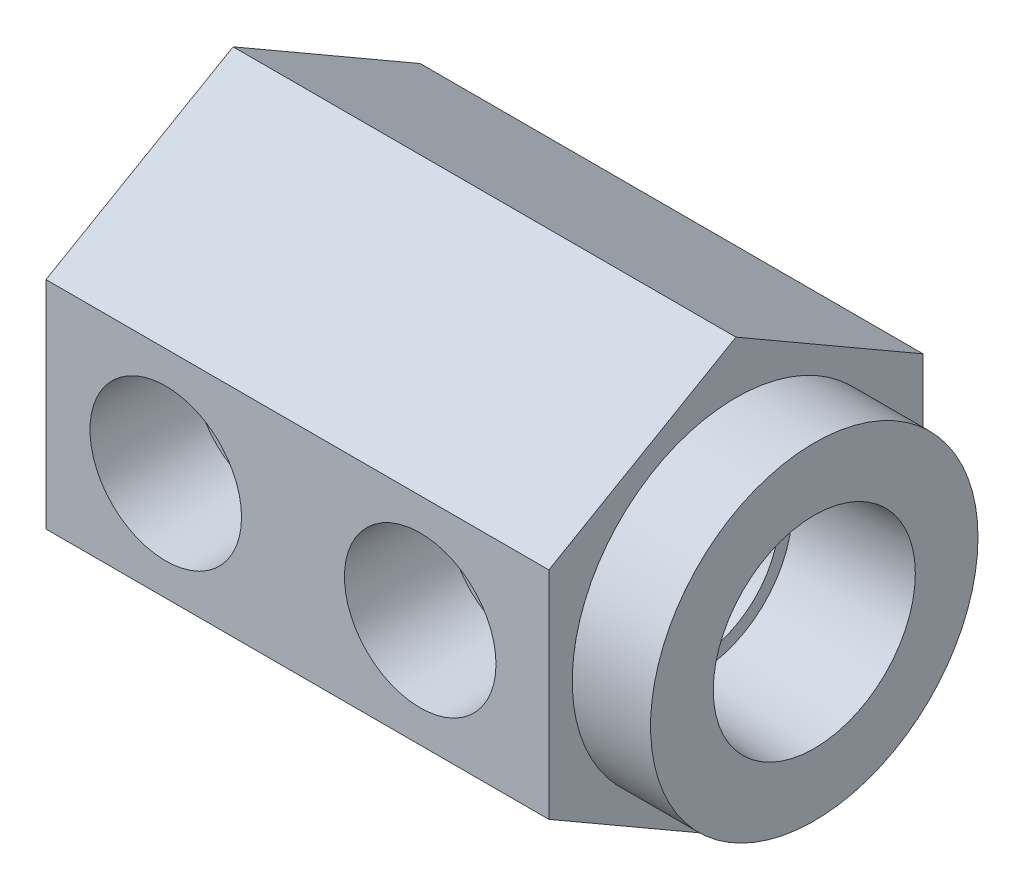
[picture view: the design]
ISO-10303-21;
HEADER;
FILE_DESCRIPTION(('STEP AP214'),'2;1');
FILE_NAME('part.step','',(''),(''),'','','');
FILE_SCHEMA(('AUTOMOTIVE_DESIGN { 1 0 10303 214 1 1 1 1 }'));
ENDSEC;
DATA;
#1=APPLICATION_CONTEXT('core data for automotive mechanical design processes');
#2=APPLICATION_PROTOCOL_DEFINITION('international standard','automotive_design',2000,#1);
#3=PRODUCT_CONTEXT('',#1,'mechanical');
#4=PRODUCT('Part','Part','',(#3));
#5=PRODUCT_RELATED_PRODUCT_CATEGORY('part','',(#4));
#6=PRODUCT_DEFINITION_FORMATION('','',#4);
#7=PRODUCT_DEFINITION_CONTEXT('part definition',#1,'design');
#8=PRODUCT_DEFINITION('design','',#6,#7);
#9=PRODUCT_DEFINITION_SHAPE('','',#8);
#10=(LENGTH_UNIT() NAMED_UNIT(*) SI_UNIT(.MILLI.,.METRE.));
#11=(NAMED_UNIT(*) PLANE_ANGLE_UNIT() SI_UNIT($,.RADIAN.));
#12=(NAMED_UNIT(*) SI_UNIT($,.STERADIAN.) SOLID_ANGLE_UNIT());
#13=UNCERTAINTY_MEASURE_WITH_UNIT(LENGTH_MEASURE(1.E-05),#10,'distance_accuracy_value','');
#14=(GEOMETRIC_REPRESENTATION_CONTEXT(3) GLOBAL_UNCERTAINTY_ASSIGNED_CONTEXT((#13)) GLOBAL_UNIT_ASSIGNED_CONTEXT((#10,
#11,#12)) REPRESENTATION_CONTEXT('',''));
#15=CARTESIAN_POINT('',(0.,0.,0.));
#16=DIRECTION('',(0.,0.,1.));
#17=DIRECTION('',(1.,0.,0.));
#18=AXIS2_PLACEMENT_3D('',#15,#16,#17);
#19=CARTESIAN_POINT('',(39.44747,0.,0.));
#20=DIRECTION('',(1.,0.,0.));
#21=DIRECTION('',(0.,0.,-1.));
#22=AXIS2_PLACEMENT_3D('',#19,#20,#21);
#23=PLANE('',#22);
#24=CARTESIAN_POINT('',(39.44747,0.,0.));
#25=DIRECTION('',(1.,0.,0.));
#26=DIRECTION('',(0.,0.,-1.));
#27=AXIS2_PLACEMENT_3D('',#24,#25,#26);
#28=CIRCLE('',#27,11.1125);
#29=CARTESIAN_POINT('',(39.44747,0.,-11.1125));
#30=VERTEX_POINT('',#29);
#31=EDGE_CURVE('E137',#30,#30,#28,.T.);
#32=ORIENTED_EDGE('',*,*,#31,.T.);
#33=EDGE_LOOP('',(#32));
#34=FACE_BOUND('',#33,.T.);
#35=CARTESIAN_POINT('',(39.44747,0.,0.));
#36=DIRECTION('',(-1.,0.,0.));
#37=DIRECTION('',(0.,0.,1.));
#38=AXIS2_PLACEMENT_3D('',#35,#36,#37);
#39=CIRCLE('',#38,6.85806655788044);
#40=CARTESIAN_POINT('',(39.44747,0.,6.85806655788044));
#41=VERTEX_POINT('',#40);
#42=EDGE_CURVE('E297',#41,#41,#39,.T.);
#43=ORIENTED_EDGE('',*,*,#42,.T.);
#44=EDGE_LOOP('',(#43));
#45=FACE_BOUND('',#44,.T.);
#46=ADVANCED_FACE('F35',(#34,#45),#23,.T.);
#47=CARTESIAN_POINT('',(34.13125,-7.33234841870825,12.7));
#48=DIRECTION('',(1.,0.,0.));
#49=DIRECTION('',(0.,0.,-1.));
#50=AXIS2_PLACEMENT_3D('',#47,#48,#49);
#51=PLANE('',#50);
#52=DIRECTION('',(0.,-1.,0.));
#53=VECTOR('',#52,1.);
#54=CARTESIAN_POINT('',(34.13125,7.33234841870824,12.7));
#55=LINE('',#54,#53);
#56=CARTESIAN_POINT('',(34.13125,7.33234841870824,12.7));
#57=VERTEX_POINT('',#56);
#58=CARTESIAN_POINT('',(34.13125,-7.33234841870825,12.7));
#59=VERTEX_POINT('',#58);
#60=EDGE_CURVE('E145',#57,#59,#55,.T.);
#61=ORIENTED_EDGE('',*,*,#60,.T.);
#62=DIRECTION('',(0.,-0.5,-0.866025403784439));
#63=VECTOR('',#62,1.);
#64=CARTESIAN_POINT('',(34.13125,-7.33234841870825,12.7));
#65=LINE('',#64,#63);
#66=CARTESIAN_POINT('',(34.13125,-14.6646968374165,0.));
#67=VERTEX_POINT('',#66);
#68=EDGE_CURVE('E95',#59,#67,#65,.T.);
#69=ORIENTED_EDGE('',*,*,#68,.T.);
#70=DIRECTION('',(0.,0.5,-0.866025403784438));
#71=VECTOR('',#70,1.);
#72=CARTESIAN_POINT('',(34.13125,-14.6646968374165,0.));
#73=LINE('',#72,#71);
#74=CARTESIAN_POINT('',(34.13125,-7.33234841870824,-12.7));
#75=VERTEX_POINT('',#74);
#76=EDGE_CURVE('E112',#67,#75,#73,.T.);
#77=ORIENTED_EDGE('',*,*,#76,.T.);
#78=DIRECTION('',(0.,1.,0.));
#79=VECTOR('',#78,1.);
#80=CARTESIAN_POINT('',(34.13125,-7.33234841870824,-12.7));
#81=LINE('',#80,#79);
#82=CARTESIAN_POINT('',(34.13125,7.33234841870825,-12.7));
#83=VERTEX_POINT('',#82);
#84=EDGE_CURVE('E104',#75,#83,#81,.T.);
#85=ORIENTED_EDGE('',*,*,#84,.T.);
#86=DIRECTION('',(0.,0.5,0.866025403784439));
#87=VECTOR('',#86,1.);
#88=CARTESIAN_POINT('',(34.13125,7.33234841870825,-12.7));
#89=LINE('',#88,#87);
#90=CARTESIAN_POINT('',(34.13125,14.6646968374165,0.));
#91=VERTEX_POINT('',#90);
#92=EDGE_CURVE('E109',#83,#91,#89,.T.);
#93=ORIENTED_EDGE('',*,*,#92,.T.);
#94=DIRECTION('',(0.,-0.5,0.866025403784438));
#95=VECTOR('',#94,1.);
#96=CARTESIAN_POINT('',(34.13125,14.6646968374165,0.));
#97=LINE('',#96,#95);
#98=EDGE_CURVE('E59',#91,#57,#97,.T.);
#99=ORIENTED_EDGE('',*,*,#98,.T.);
#100=EDGE_LOOP('',(#61,#69,#77,#85,#93,#99));
#101=FACE_BOUND('',#100,.T.);
#102=CARTESIAN_POINT('',(34.13125,0.,0.));
#103=DIRECTION('',(1.,0.,0.));
#104=DIRECTION('',(0.,0.,-1.));
#105=AXIS2_PLACEMENT_3D('',#102,#103,#104);
#106=CIRCLE('',#105,11.1125);
#107=CARTESIAN_POINT('',(34.13125,0.,-11.1125));
#108=VERTEX_POINT('',#107);
#109=EDGE_CURVE('E290',#108,#108,#106,.T.);
#110=ORIENTED_EDGE('',*,*,#109,.F.);
#111=EDGE_LOOP('',(#110));
#112=FACE_BOUND('',#111,.T.);
#113=ADVANCED_FACE('F106',(#101,#112),#51,.T.);
#114=CARTESIAN_POINT('',(34.13125,7.33234841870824,12.7));
#115=DIRECTION('',(0.,0.,-1.));
#116=DIRECTION('',(0.,1.,0.));
#117=AXIS2_PLACEMENT_3D('',#114,#115,#116);
#118=PLANE('',#117);
#119=CARTESIAN_POINT('',(8.128,0.,12.7));
#120=DIRECTION('',(0.,0.,1.));
#121=DIRECTION('',(1.,0.,0.));
#122=AXIS2_PLACEMENT_3D('',#119,#120,#121);
#123=CIRCLE('',#122,5.1435);
#124=CARTESIAN_POINT('',(13.2715,0.,12.7));
#125=VERTEX_POINT('',#124);
#126=EDGE_CURVE('E319',#125,#125,#123,.T.);
#127=ORIENTED_EDGE('',*,*,#126,.F.);
#128=EDGE_LOOP('',(#127));
#129=FACE_BOUND('',#128,.T.);
#130=CARTESIAN_POINT('',(25.4,0.,12.7));
#131=DIRECTION('',(0.,0.,1.));
#132=DIRECTION('',(1.,0.,0.));
#133=AXIS2_PLACEMENT_3D('',#130,#131,#132);
#134=CIRCLE('',#133,5.1435);
#135=CARTESIAN_POINT('',(30.5435,0.,12.7));
#136=VERTEX_POINT('',#135);
#137=EDGE_CURVE('E310',#136,#136,#134,.T.);
#138=ORIENTED_EDGE('',*,*,#137,.F.);
#139=EDGE_LOOP('',(#138));
#140=FACE_BOUND('',#139,.T.);
#141=DIRECTION('',(0.,-1.,0.));
#142=VECTOR('',#141,1.);
#143=CARTESIAN_POINT('',(0.,7.33234841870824,12.7));
#144=LINE('',#143,#142);
#145=CARTESIAN_POINT('',(0.,7.33234841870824,12.7));
#146=VERTEX_POINT('',#145);
#147=CARTESIAN_POINT('',(0.,-7.33234841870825,12.7));
#148=VERTEX_POINT('',#147);
#149=EDGE_CURVE('E133',#146,#148,#144,.T.);
#150=ORIENTED_EDGE('',*,*,#149,.T.);
#151=DIRECTION('',(-1.,0.,0.));
#152=VECTOR('',#151,1.);
#153=CARTESIAN_POINT('',(34.13125,-7.33234841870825,12.7));
#154=LINE('',#153,#152);
#155=EDGE_CURVE('E152',#59,#148,#154,.T.);
#156=ORIENTED_EDGE('',*,*,#155,.F.);
#157=ORIENTED_EDGE('',*,*,#60,.F.);
#158=DIRECTION('',(-1.,0.,0.));
#159=VECTOR('',#158,1.);
#160=CARTESIAN_POINT('',(34.13125,7.33234841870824,12.7));
#161=LINE('',#160,#159);
#162=EDGE_CURVE('E129',#57,#146,#161,.T.);
#163=ORIENTED_EDGE('',*,*,#162,.T.);
#164=EDGE_LOOP('',(#150,#156,#157,#163));
#165=FACE_BOUND('',#164,.T.);
#166=ADVANCED_FACE('F37',(#129,#140,#165),#118,.F.);
#167=CARTESIAN_POINT('',(34.13125,-7.33234841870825,12.7));
#168=DIRECTION('',(0.,0.866025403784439,-0.5));
#169=DIRECTION('',(0.,0.5,0.866025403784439));
#170=AXIS2_PLACEMENT_3D('',#167,#168,#169);
#171=PLANE('',#170);
#172=DIRECTION('',(0.,-0.5,-0.866025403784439));
#173=VECTOR('',#172,1.);
#174=CARTESIAN_POINT('',(0.,-7.33234841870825,12.7));
#175=LINE('',#174,#173);
#176=CARTESIAN_POINT('',(0.,-14.6646968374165,0.));
#177=VERTEX_POINT('',#176);
#178=EDGE_CURVE('E136',#148,#177,#175,.T.);
#179=ORIENTED_EDGE('',*,*,#178,.T.);
#180=DIRECTION('',(-1.,0.,0.));
#181=VECTOR('',#180,1.);
#182=CARTESIAN_POINT('',(34.13125,-14.6646968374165,0.));
#183=LINE('',#182,#181);
#184=EDGE_CURVE('E149',#67,#177,#183,.T.);
#185=ORIENTED_EDGE('',*,*,#184,.F.);
#186=ORIENTED_EDGE('',*,*,#68,.F.);
#187=ORIENTED_EDGE('',*,*,#155,.T.);
#188=EDGE_LOOP('',(#179,#185,#186,#187));
#189=FACE_BOUND('',#188,.T.);
#190=ADVANCED_FACE('F275',(#189),#171,.F.);
#191=CARTESIAN_POINT('',(34.13125,-14.6646968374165,0.));
#192=DIRECTION('',(0.,0.866025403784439,0.5));
#193=DIRECTION('',(0.,-0.5,0.866025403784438));
#194=AXIS2_PLACEMENT_3D('',#191,#192,#193);
#195=PLANE('',#194);
#196=DIRECTION('',(0.,0.5,-0.866025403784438));
#197=VECTOR('',#196,1.);
#198=CARTESIAN_POINT('',(0.,-14.6646968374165,0.));
#199=LINE('',#198,#197);
#200=CARTESIAN_POINT('',(0.,-7.33234841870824,-12.7));
#201=VERTEX_POINT('',#200);
#202=EDGE_CURVE('E139',#177,#201,#199,.T.);
#203=ORIENTED_EDGE('',*,*,#202,.T.);
#204=DIRECTION('',(-1.,0.,0.));
#205=VECTOR('',#204,1.);
#206=CARTESIAN_POINT('',(34.13125,-7.33234841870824,-12.7));
#207=LINE('',#206,#205);
#208=EDGE_CURVE('E124',#75,#201,#207,.T.);
#209=ORIENTED_EDGE('',*,*,#208,.F.);
#210=ORIENTED_EDGE('',*,*,#76,.F.);
#211=ORIENTED_EDGE('',*,*,#184,.T.);
#212=EDGE_LOOP('',(#203,#209,#210,#211));
#213=FACE_BOUND('',#212,.T.);
#214=ADVANCED_FACE('F272',(#213),#195,.F.);
#215=CARTESIAN_POINT('',(34.13125,-7.33234841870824,-12.7));
#216=DIRECTION('',(0.,0.,1.));
#217=DIRECTION('',(0.,-1.,0.));
#218=AXIS2_PLACEMENT_3D('',#215,#216,#217);
#219=PLANE('',#218);
#220=CARTESIAN_POINT('',(8.128,0.,-12.7));
#221=DIRECTION('',(0.,0.,-1.));
#222=DIRECTION('',(0.,1.,0.));
#223=AXIS2_PLACEMENT_3D('',#220,#221,#222);
#224=CIRCLE('',#223,5.1435);
#225=CARTESIAN_POINT('',(8.128,5.1435,-12.7));
#226=VERTEX_POINT('',#225);
#227=EDGE_CURVE('E328',#226,#226,#224,.T.);
#228=ORIENTED_EDGE('',*,*,#227,.F.);
#229=EDGE_LOOP('',(#228));
#230=FACE_BOUND('',#229,.T.);
#231=DIRECTION('',(0.,1.,0.));
#232=VECTOR('',#231,1.);
#233=CARTESIAN_POINT('',(0.,-7.33234841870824,-12.7));
#234=LINE('',#233,#232);
#235=CARTESIAN_POINT('',(0.,7.33234841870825,-12.7));
#236=VERTEX_POINT('',#235);
#237=EDGE_CURVE('E121',#201,#236,#234,.T.);
#238=ORIENTED_EDGE('',*,*,#237,.T.);
#239=DIRECTION('',(-1.,0.,0.));
#240=VECTOR('',#239,1.);
#241=CARTESIAN_POINT('',(34.13125,7.33234841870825,-12.7));
#242=LINE('',#241,#240);
#243=EDGE_CURVE('E118',#83,#236,#242,.T.);
#244=ORIENTED_EDGE('',*,*,#243,.F.);
#245=ORIENTED_EDGE('',*,*,#84,.F.);
#246=ORIENTED_EDGE('',*,*,#208,.T.);
#247=EDGE_LOOP('',(#238,#244,#245,#246));
#248=FACE_BOUND('',#247,.T.);
#249=ADVANCED_FACE('F119',(#230,#248),#219,.F.);
#250=CARTESIAN_POINT('',(34.13125,7.33234841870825,-12.7));
#251=DIRECTION('',(0.,-0.866025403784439,0.5));
#252=DIRECTION('',(0.,-0.5,-0.866025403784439));
#253=AXIS2_PLACEMENT_3D('',#250,#251,#252);
#254=PLANE('',#253);
#255=DIRECTION('',(0.,0.5,0.866025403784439));
#256=VECTOR('',#255,1.);
#257=CARTESIAN_POINT('',(0.,7.33234841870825,-12.7));
#258=LINE('',#257,#256);
#259=CARTESIAN_POINT('',(0.,14.6646968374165,0.));
#260=VERTEX_POINT('',#259);
#261=EDGE_CURVE('E142',#236,#260,#258,.T.);
#262=ORIENTED_EDGE('',*,*,#261,.T.);
#263=DIRECTION('',(-1.,0.,0.));
#264=VECTOR('',#263,1.);
#265=CARTESIAN_POINT('',(34.13125,14.6646968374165,0.));
#266=LINE('',#265,#264);
#267=EDGE_CURVE('E125',#91,#260,#266,.T.);
#268=ORIENTED_EDGE('',*,*,#267,.F.);
#269=ORIENTED_EDGE('',*,*,#92,.F.);
#270=ORIENTED_EDGE('',*,*,#243,.T.);
#271=EDGE_LOOP('',(#262,#268,#269,#270));
#272=FACE_BOUND('',#271,.T.);
#273=ADVANCED_FACE('F127',(#272),#254,.F.);
#274=CARTESIAN_POINT('',(34.13125,14.6646968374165,0.));
#275=DIRECTION('',(0.,-0.866025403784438,-0.5));
#276=DIRECTION('',(0.,0.5,-0.866025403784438));
#277=AXIS2_PLACEMENT_3D('',#274,#275,#276);
#278=PLANE('',#277);
#279=DIRECTION('',(0.,-0.5,0.866025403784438));
#280=VECTOR('',#279,1.);
#281=CARTESIAN_POINT('',(0.,14.6646968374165,0.));
#282=LINE('',#281,#280);
#283=EDGE_CURVE('E86',#260,#146,#282,.T.);
#284=ORIENTED_EDGE('',*,*,#283,.T.);
#285=ORIENTED_EDGE('',*,*,#162,.F.);
#286=ORIENTED_EDGE('',*,*,#98,.F.);
#287=ORIENTED_EDGE('',*,*,#267,.T.);
#288=EDGE_LOOP('',(#284,#285,#286,#287));
#289=FACE_BOUND('',#288,.T.);
#290=ADVANCED_FACE('F264',(#289),#278,.F.);
#291=CARTESIAN_POINT('',(0.,-7.33234841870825,12.7));
#292=DIRECTION('',(1.,0.,0.));
#293=DIRECTION('',(0.,0.,-1.));
#294=AXIS2_PLACEMENT_3D('',#291,#292,#293);
#295=PLANE('',#294);
#296=ORIENTED_EDGE('',*,*,#149,.F.);
#297=ORIENTED_EDGE('',*,*,#283,.F.);
#298=ORIENTED_EDGE('',*,*,#261,.F.);
#299=ORIENTED_EDGE('',*,*,#237,.F.);
#300=ORIENTED_EDGE('',*,*,#202,.F.);
#301=ORIENTED_EDGE('',*,*,#178,.F.);
#302=EDGE_LOOP('',(#296,#297,#298,#299,#300,#301));
#303=FACE_BOUND('',#302,.T.);
#304=ADVANCED_FACE('F259',(#303),#295,.F.);
#305=CARTESIAN_POINT('',(39.44747,0.,0.));
#306=DIRECTION('',(-1.,0.,0.));
#307=DIRECTION('',(0.,0.,1.));
#308=AXIS2_PLACEMENT_3D('',#305,#306,#307);
#309=CYLINDRICAL_SURFACE('',#308,11.1125);
#310=ORIENTED_EDGE('',*,*,#31,.F.);
#311=EDGE_LOOP('',(#310));
#312=FACE_BOUND('',#311,.T.);
#313=ORIENTED_EDGE('',*,*,#109,.T.);
#314=EDGE_LOOP('',(#313));
#315=FACE_BOUND('',#314,.T.);
#316=ADVANCED_FACE('F257',(#312,#315),#309,.T.);
#317=CARTESIAN_POINT('',(31.50997,5.55625,0.));
#318=DIRECTION('',(1.,0.,0.));
#319=DIRECTION('',(0.,0.,-1.));
#320=AXIS2_PLACEMENT_3D('',#317,#318,#319);
#321=PLANE('',#320);
#322=CARTESIAN_POINT('',(31.50997,0.,0.));
#323=DIRECTION('',(-1.,0.,0.));
#324=DIRECTION('',(0.,0.,1.));
#325=AXIS2_PLACEMENT_3D('',#322,#323,#324);
#326=CIRCLE('',#325,5.55625);
#327=CARTESIAN_POINT('',(31.50997,0.,5.55625));
#328=VERTEX_POINT('',#327);
#329=EDGE_CURVE('E163',#328,#328,#326,.T.);
#330=ORIENTED_EDGE('',*,*,#329,.T.);
#331=EDGE_LOOP('',(#330));
#332=FACE_BOUND('',#331,.T.);
#333=CARTESIAN_POINT('',(31.50997,0.,0.));
#334=DIRECTION('',(-1.,0.,0.));
#335=DIRECTION('',(0.,0.,1.));
#336=AXIS2_PLACEMENT_3D('',#333,#334,#335);
#337=CIRCLE('',#336,6.44207980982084);
#338=CARTESIAN_POINT('',(31.50997,0.,6.44207980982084));
#339=VERTEX_POINT('',#338);
#340=EDGE_CURVE('E293',#339,#339,#337,.T.);
#341=ORIENTED_EDGE('',*,*,#340,.F.);
#342=EDGE_LOOP('',(#341));
#343=FACE_BOUND('',#342,.T.);
#344=ADVANCED_FACE('F255',(#332,#343),#321,.T.);
#345=CARTESIAN_POINT('',(39.44747,0.,0.));
#346=DIRECTION('',(1.,0.,0.));
#347=DIRECTION('',(0.,0.,-1.));
#348=AXIS2_PLACEMENT_3D('',#345,#346,#347);
#349=CONICAL_SURFACE('',#348,6.85806655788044,0.0523598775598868);
#350=ORIENTED_EDGE('',*,*,#340,.T.);
#351=EDGE_LOOP('',(#350));
#352=FACE_BOUND('',#351,.T.);
#353=ORIENTED_EDGE('',*,*,#42,.F.);
#354=EDGE_LOOP('',(#353));
#355=FACE_BOUND('',#354,.T.);
#356=ADVANCED_FACE('F355',(#352,#355),#349,.F.);
#357=CARTESIAN_POINT('',(21.03247,0.,0.));
#358=DIRECTION('',(1.,0.,0.));
#359=DIRECTION('',(0.,0.,-1.));
#360=AXIS2_PLACEMENT_3D('',#357,#358,#359);
#361=PLANE('',#360);
#362=CARTESIAN_POINT('',(21.03247,0.,0.));
#363=DIRECTION('',(1.,0.,0.));
#364=DIRECTION('',(0.,0.,-1.));
#365=AXIS2_PLACEMENT_3D('',#362,#363,#364);
#366=CIRCLE('',#365,3.96875);
#367=CARTESIAN_POINT('',(21.03247,0.,-3.96875));
#368=VERTEX_POINT('',#367);
#369=EDGE_CURVE('E39',#368,#368,#366,.T.);
#370=ORIENTED_EDGE('',*,*,#369,.F.);
#371=EDGE_LOOP('',(#370));
#372=FACE_BOUND('',#371,.T.);
#373=CARTESIAN_POINT('',(21.03247,0.,0.));
#374=DIRECTION('',(-1.,0.,0.));
#375=DIRECTION('',(0.,0.,1.));
#376=AXIS2_PLACEMENT_3D('',#373,#374,#375);
#377=CIRCLE('',#376,5.55625);
#378=CARTESIAN_POINT('',(21.03247,0.,5.55625));
#379=VERTEX_POINT('',#378);
#380=EDGE_CURVE('E300',#379,#379,#377,.T.);
#381=ORIENTED_EDGE('',*,*,#380,.F.);
#382=EDGE_LOOP('',(#381));
#383=FACE_BOUND('',#382,.T.);
#384=ADVANCED_FACE('F352',(#372,#383),#361,.T.);
#385=CARTESIAN_POINT('',(0.,0.,0.));
#386=DIRECTION('',(-1.,0.,0.));
#387=DIRECTION('',(0.,0.,1.));
#388=AXIS2_PLACEMENT_3D('',#385,#386,#387);
#389=CYLINDRICAL_SURFACE('',#388,5.55625);
#390=CARTESIAN_POINT('',(29.6164,0.,5.55625));
#391=CARTESIAN_POINT('',(29.6163993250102,-0.102693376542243,5.55624935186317));
#392=CARTESIAN_POINT('',(29.6126418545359,-0.205397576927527,5.55339643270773));
#393=CARTESIAN_POINT('',(29.5976742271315,-0.409987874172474,5.54205114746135));
#394=CARTESIAN_POINT('',(29.586460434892,-0.511873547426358,5.53355603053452));
#395=CARTESIAN_POINT('',(29.5567421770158,-0.714130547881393,5.51110649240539));
#396=CARTESIAN_POINT('',(29.5382264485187,-0.814499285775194,5.49714363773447));
#397=CARTESIAN_POINT('',(29.4942051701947,-1.01284455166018,5.46408215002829));
#398=CARTESIAN_POINT('',(29.4686965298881,-1.11082000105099,5.44498124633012));
#399=CARTESIAN_POINT('',(29.3825831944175,-1.39891797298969,5.38083315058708));
#400=CARTESIAN_POINT('',(29.3121704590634,-1.58466430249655,5.32877063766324));
#401=CARTESIAN_POINT('',(29.1485378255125,-1.94034128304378,5.20982470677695));
#402=CARTESIAN_POINT('',(29.0553219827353,-2.11027473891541,5.1429439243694));
#403=CARTESIAN_POINT('',(28.8395703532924,-2.44767830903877,4.99179767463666));
#404=CARTESIAN_POINT('',(28.7151124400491,-2.61344503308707,4.90649322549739));
#405=CARTESIAN_POINT('',(28.445557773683,-2.92315956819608,4.72852964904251));
#406=CARTESIAN_POINT('',(28.300430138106,-3.06707405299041,4.63585961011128));
#407=CARTESIAN_POINT('',(28.0527623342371,-3.27963118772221,4.48615059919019));
#408=CARTESIAN_POINT('',(27.9560898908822,-3.35552727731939,4.42952031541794));
#409=CARTESIAN_POINT('',(27.7560755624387,-3.49886885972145,4.31718819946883));
#410=CARTESIAN_POINT('',(27.6527316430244,-3.56631175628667,4.26148665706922));
#411=CARTESIAN_POINT('',(27.4395786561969,-3.69235121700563,4.15275532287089));
#412=CARTESIAN_POINT('',(27.3297756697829,-3.75095592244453,4.09972310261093));
#413=CARTESIAN_POINT('',(27.1037486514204,-3.85888092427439,3.99830378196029));
#414=CARTESIAN_POINT('',(26.9875283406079,-3.90820652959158,3.94991403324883));
#415=CARTESIAN_POINT('',(26.7125548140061,-4.01032101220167,3.84655569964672));
#416=CARTESIAN_POINT('',(26.5515353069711,-4.05967723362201,3.79399633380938));
#417=CARTESIAN_POINT('',(26.3032358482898,-4.11939822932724,3.72871892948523));
#418=CARTESIAN_POINT('',(26.2193920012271,-4.13691360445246,3.70922751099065));
#419=CARTESIAN_POINT('',(26.0497879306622,-4.1669184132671,3.67548846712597));
#420=CARTESIAN_POINT('',(25.9640287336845,-4.17941047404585,3.66123810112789));
#421=CARTESIAN_POINT('',(25.7902465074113,-4.19922159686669,3.63850031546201));
#422=CARTESIAN_POINT('',(25.702209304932,-4.20648654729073,3.63007321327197));
#423=CARTESIAN_POINT('',(25.5254696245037,-4.21546136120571,3.61964744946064));
#424=CARTESIAN_POINT('',(25.4367671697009,-4.21717141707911,3.61764856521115));
#425=CARTESIAN_POINT('',(25.25950294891,-4.21499058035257,3.62018953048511));
#426=CARTESIAN_POINT('',(25.1709412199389,-4.21109840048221,3.62473088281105));
#427=CARTESIAN_POINT('',(24.9948050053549,-4.19781579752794,3.64010347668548));
#428=CARTESIAN_POINT('',(24.9072305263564,-4.18842533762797,3.65093476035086));
#429=CARTESIAN_POINT('',(24.6670671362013,-4.15509038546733,3.68893056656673));
#430=CARTESIAN_POINT('',(24.5161923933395,-4.12550713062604,3.72225050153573));
#431=CARTESIAN_POINT('',(24.2220882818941,-4.05137671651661,3.80278947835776));
#432=CARTESIAN_POINT('',(24.0788668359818,-4.00681438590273,3.85002260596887));
#433=CARTESIAN_POINT('',(23.8260179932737,-3.91348438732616,3.94463534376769));
#434=CARTESIAN_POINT('',(23.7149764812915,-3.86690895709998,3.99046546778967));
#435=CARTESIAN_POINT('',(23.4987398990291,-3.76530472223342,4.08647520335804));
#436=CARTESIAN_POINT('',(23.3935479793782,-3.71027142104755,4.13665712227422));
#437=CARTESIAN_POINT('',(23.1888896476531,-3.59207638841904,4.2397008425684));
#438=CARTESIAN_POINT('',(23.0894357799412,-3.52889775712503,4.29256807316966));
#439=CARTESIAN_POINT('',(22.896560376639,-3.39479221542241,4.39939220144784));
#440=CARTESIAN_POINT('',(22.8031378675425,-3.32386656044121,4.45334892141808));
#441=CARTESIAN_POINT('',(22.6198789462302,-3.17229987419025,4.56260828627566));
#442=CARTESIAN_POINT('',(22.5302195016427,-3.09144027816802,4.61790568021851));
#443=CARTESIAN_POINT('',(22.3577105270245,-2.92184039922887,4.72704545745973));
#444=CARTESIAN_POINT('',(22.274863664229,-2.83309705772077,4.78088726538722));
#445=CARTESIAN_POINT('',(22.0375306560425,-2.55557286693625,4.93821773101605));
#446=CARTESIAN_POINT('',(21.893717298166,-2.3550581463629,5.03784133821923));
#447=CARTESIAN_POINT('',(21.6649881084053,-1.96676092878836,5.19991035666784));
#448=CARTESIAN_POINT('',(21.5740623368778,-1.783982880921,5.26582042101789));
#449=CARTESIAN_POINT('',(21.4573057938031,-1.49794068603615,5.35145144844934));
#450=CARTESIAN_POINT('',(21.421651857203,-1.40058567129,5.37779487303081));
#451=CARTESIAN_POINT('',(21.3573496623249,-1.20243166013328,5.42553595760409));
#452=CARTESIAN_POINT('',(21.3286983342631,-1.10163419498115,5.44693578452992));
#453=CARTESIAN_POINT('',(21.2786470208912,-0.896496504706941,5.48444704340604));
#454=CARTESIAN_POINT('',(21.2573003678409,-0.792136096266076,5.50051955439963));
#455=CARTESIAN_POINT('',(21.2225152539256,-0.581416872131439,5.52676517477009));
#456=CARTESIAN_POINT('',(21.2090731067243,-0.475059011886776,5.53694103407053));
#457=CARTESIAN_POINT('',(21.1903325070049,-0.261235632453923,5.55113934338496));
#458=CARTESIAN_POINT('',(21.1850326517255,-0.1537703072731,5.55516285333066));
#459=CARTESIAN_POINT('',(21.1826743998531,0.0612961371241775,5.5569523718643));
#460=CARTESIAN_POINT('',(21.1856152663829,0.168897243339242,5.55471893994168));
#461=CARTESIAN_POINT('',(21.1989208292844,0.371674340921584,5.5446311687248));
#462=CARTESIAN_POINT('',(21.2084499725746,0.466937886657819,5.53740954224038));
#463=CARTESIAN_POINT('',(21.2338694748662,0.656134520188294,5.51819377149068));
#464=CARTESIAN_POINT('',(21.2497618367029,0.750067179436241,5.50619812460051));
#465=CARTESIAN_POINT('',(21.3066724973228,1.0288748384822,5.46338413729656));
#466=CARTESIAN_POINT('',(21.356935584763,1.21092313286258,5.42573004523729));
#467=CARTESIAN_POINT('',(21.4812624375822,1.56789963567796,5.33372302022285));
#468=CARTESIAN_POINT('',(21.5559374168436,1.74249866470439,5.27894302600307));
#469=CARTESIAN_POINT('',(21.7256433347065,2.07659649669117,5.15667714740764));
#470=CARTESIAN_POINT('',(21.8206773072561,2.23609304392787,5.08918936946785));
#471=CARTESIAN_POINT('',(22.0455518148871,2.56347572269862,4.93341300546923));
#472=CARTESIAN_POINT('',(22.1785466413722,2.72842274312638,4.8435290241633));
#473=CARTESIAN_POINT('',(22.4657559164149,3.03521371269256,4.65742624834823));
#474=CARTESIAN_POINT('',(22.6200134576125,3.17700943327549,4.56119480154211));
#475=CARTESIAN_POINT('',(22.8821039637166,3.38436105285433,4.40765179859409));
#476=CARTESIAN_POINT('',(22.9837901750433,3.45770845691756,4.35018681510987));
#477=CARTESIAN_POINT('',(23.1940490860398,3.59549974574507,4.23700773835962));
#478=CARTESIAN_POINT('',(23.3026242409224,3.65994042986,4.18129428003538));
#479=CARTESIAN_POINT('',(23.5263714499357,3.77936334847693,4.07366880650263));
#480=CARTESIAN_POINT('',(23.6415306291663,3.8343632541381,4.02174979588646));
#481=CARTESIAN_POINT('',(23.8784440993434,3.93439147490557,3.92394754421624));
#482=CARTESIAN_POINT('',(24.0001932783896,3.97942738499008,3.8780597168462));
#483=CARTESIAN_POINT('',(24.2790144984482,4.06784554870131,3.78544072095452));
#484=CARTESIAN_POINT('',(24.4377707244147,4.10846555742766,3.74094260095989));
#485=CARTESIAN_POINT('',(24.6813970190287,4.15553716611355,3.6883562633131));
#486=CARTESIAN_POINT('',(24.7634690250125,4.16891399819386,3.67319259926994));
#487=CARTESIAN_POINT('',(24.9290383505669,4.19084532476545,3.64815156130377));
#488=CARTESIAN_POINT('',(25.0125349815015,4.19940208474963,3.63827170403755));
#489=CARTESIAN_POINT('',(25.1809809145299,4.21156059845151,3.62419089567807));
#490=CARTESIAN_POINT('',(25.2659363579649,4.21512601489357,3.62003159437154));
#491=CARTESIAN_POINT('',(25.4359878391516,4.21710364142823,3.61772767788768));
#492=CARTESIAN_POINT('',(25.5210838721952,4.21551602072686,3.61958286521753));
#493=CARTESIAN_POINT('',(25.69074369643,4.20722188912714,3.629219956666));
#494=CARTESIAN_POINT('',(25.7753070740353,4.20051180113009,3.63700600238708));
#495=CARTESIAN_POINT('',(25.9432169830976,4.1821148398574,3.65814491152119));
#496=CARTESIAN_POINT('',(26.0265628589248,4.17042538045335,3.67150066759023));
#497=CARTESIAN_POINT('',(26.2053377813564,4.13992798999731,3.70587659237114));
#498=CARTESIAN_POINT('',(26.3004441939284,4.1202540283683,3.72780747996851));
#499=CARTESIAN_POINT('',(26.4876880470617,4.07483267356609,3.77740472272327));
#500=CARTESIAN_POINT('',(26.5798232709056,4.0490808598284,3.80507525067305));
#501=CARTESIAN_POINT('',(26.8515481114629,3.9632252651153,3.89507311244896));
#502=CARTESIAN_POINT('',(27.0262161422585,3.89456404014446,3.9643352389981));
#503=CARTESIAN_POINT('',(27.3096983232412,3.76132382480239,4.0902354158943));
#504=CARTESIAN_POINT('',(27.4222798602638,3.70195130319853,4.14423023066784));
#505=CARTESIAN_POINT('',(27.6406852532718,3.57398466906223,4.25507997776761));
#506=CARTESIAN_POINT('',(27.7465066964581,3.50538729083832,4.31193591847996));
#507=CARTESIAN_POINT('',(27.9513183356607,3.35926316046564,4.42672704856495));
#508=CARTESIAN_POINT('',(28.0503021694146,3.28172826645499,4.48466318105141));
#509=CARTESIAN_POINT('',(28.2411263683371,3.11798488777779,4.60001225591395));
#510=CARTESIAN_POINT('',(28.332967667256,3.03177754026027,4.65742526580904));
#511=CARTESIAN_POINT('',(28.5103676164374,2.84956733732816,4.77111867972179));
#512=CARTESIAN_POINT('',(28.5958206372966,2.75344451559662,4.82737207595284));
#513=CARTESIAN_POINT('',(28.7584200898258,2.55259396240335,4.93652120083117));
#514=CARTESIAN_POINT('',(28.8355654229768,2.44786509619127,4.98941648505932));
#515=CARTESIAN_POINT('',(28.9806112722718,2.23031622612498,5.09037894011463));
#516=CARTESIAN_POINT('',(29.048528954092,2.11751185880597,5.13845503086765));
#517=CARTESIAN_POINT('',(29.1743228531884,1.88416115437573,5.22852473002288));
#518=CARTESIAN_POINT('',(29.232203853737,1.76361854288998,5.27052123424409));
#519=CARTESIAN_POINT('',(29.3221097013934,1.55061985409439,5.3363074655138));
#520=CARTESIAN_POINT('',(29.3568210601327,1.45984111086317,5.36189016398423));
#521=CARTESIAN_POINT('',(29.420152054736,1.27512063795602,5.40879414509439));
#522=CARTESIAN_POINT('',(29.448773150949,1.18117967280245,5.43011644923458));
#523=CARTESIAN_POINT('',(29.4995054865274,0.990840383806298,5.46804785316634));
#524=CARTESIAN_POINT('',(29.5216302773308,0.894447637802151,5.48466676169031));
#525=CARTESIAN_POINT('',(29.5591251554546,0.699668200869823,5.51289892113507));
#526=CARTESIAN_POINT('',(29.5744981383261,0.601282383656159,5.52451431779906));
#527=CARTESIAN_POINT('',(29.5963476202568,0.419165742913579,5.54104473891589));
#528=CARTESIAN_POINT('',(29.6038584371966,0.335627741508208,5.54673779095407));
#529=CARTESIAN_POINT('',(29.6138854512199,0.168062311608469,5.55434110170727));
#530=CARTESIAN_POINT('',(29.6164005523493,0.0840347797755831,5.55625053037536));
#531=CARTESIAN_POINT('',(29.6164,0.,5.55625));
#532=B_SPLINE_CURVE_WITH_KNOTS('',3,(#390,#391,#392,#393,#394,#395,#396,#397,#398,#399,#400,
#401,#402,#403,#404,#405,#406,#407,#408,#409,#410,#411,#412,#413,#414,#415,#416,#417,#418,#419,
#420,#421,#422,#423,#424,#425,#426,#427,#428,#429,#430,#431,#432,#433,#434,#435,#436,#437,#438,
#439,#440,#441,#442,#443,#444,#445,#446,#447,#448,#449,#450,#451,#452,#453,#454,#455,#456,#457,
#458,#459,#460,#461,#462,#463,#464,#465,#466,#467,#468,#469,#470,#471,#472,#473,#474,#475,#476,
#477,#478,#479,#480,#481,#482,#483,#484,#485,#486,#487,#488,#489,#490,#491,#492,#493,#494,#495,
#496,#497,#498,#499,#500,#501,#502,#503,#504,#505,#506,#507,#508,#509,#510,#511,#512,#513,#514,
#515,#516,#517,#518,#519,#520,#521,#522,#523,#524,#525,#526,#527,#528,#529,#530,#531),
.UNSPECIFIED.,.T.,.F.,(4,2,2,2,2,2,2,2,2,2,2,2,2,2,2,2,2,2,2,2,2,2,2,2,2,2,2,2,2,2,2,2,2,2,2,2,
2,2,2,2,2,2,2,2,2,2,2,2,2,2,2,2,2,2,2,2,2,2,2,2,2,2,2,2,2,2,2,2,2,2,4),(0.,0.307991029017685,
0.616132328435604,0.924750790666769,1.2335058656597,1.84663803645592,2.459661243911,
3.12977733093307,3.80090534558,4.20650775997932,4.61223444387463,5.01758508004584,
5.42270308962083,5.94985658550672,6.21312560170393,6.47625675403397,6.74207413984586,
7.00788231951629,7.27375158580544,7.53962263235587,8.00965097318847,8.48015681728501,
8.86617029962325,9.25238971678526,9.63942375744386,10.0263951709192,10.4243466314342,
10.8224531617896,11.6163911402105,12.2571875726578,12.5777622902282,12.8981962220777,
13.2209221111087,13.5434973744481,13.8660170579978,14.1885079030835,14.4761906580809,
14.7639640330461,15.3390242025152,15.9297539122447,16.5205717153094,17.2086216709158,
17.8980871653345,18.3114499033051,18.7249608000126,19.1376890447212,19.5501015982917,
20.057359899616,20.3106781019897,20.563877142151,20.8189100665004,21.0739346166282,
21.3291374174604,21.5844729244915,21.8827088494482,22.1811623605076,22.7788098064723,
23.1931606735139,23.6076586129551,24.0225371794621,24.4373614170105,24.857977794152,
25.2786497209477,25.6985280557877,26.118205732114,26.4194112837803,26.720544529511,
27.021045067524,27.3214166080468,27.5733927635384,27.8254241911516),.UNSPECIFIED.);
#533=CARTESIAN_POINT('',(29.6164,0.,5.55625));
#534=VERTEX_POINT('',#533);
#535=EDGE_CURVE('E155',#534,#534,#532,.T.);
#536=ORIENTED_EDGE('',*,*,#535,.F.);
#537=EDGE_LOOP('',(#536));
#538=FACE_BOUND('',#537,.T.);
#539=ORIENTED_EDGE('',*,*,#380,.T.);
#540=EDGE_LOOP('',(#539));
#541=FACE_BOUND('',#540,.T.);
#542=ORIENTED_EDGE('',*,*,#329,.F.);
#543=EDGE_LOOP('',(#542));
#544=FACE_BOUND('',#543,.T.);
#545=ADVANCED_FACE('F172',(#538,#541,#544),#389,.F.);
#546=CARTESIAN_POINT('',(25.4,0.,12.7));
#547=DIRECTION('',(0.,0.,1.));
#548=DIRECTION('',(1.,0.,0.));
#549=AXIS2_PLACEMENT_3D('',#546,#547,#548);
#550=CYLINDRICAL_SURFACE('',#549,4.2164);
#551=ORIENTED_EDGE('',*,*,#535,.T.);
#552=EDGE_LOOP('',(#551));
#553=FACE_BOUND('',#552,.T.);
#554=CARTESIAN_POINT('',(25.4,0.,5.77596));
#555=DIRECTION('',(0.,0.,1.));
#556=DIRECTION('',(1.,0.,0.));
#557=AXIS2_PLACEMENT_3D('',#554,#555,#556);
#558=CIRCLE('',#557,4.2164);
#559=CARTESIAN_POINT('',(29.6164,0.,5.77596));
#560=VERTEX_POINT('',#559);
#561=EDGE_CURVE('E164',#560,#560,#558,.T.);
#562=ORIENTED_EDGE('',*,*,#561,.T.);
#563=EDGE_LOOP('',(#562));
#564=FACE_BOUND('',#563,.T.);
#565=ADVANCED_FACE('F175',(#553,#564),#550,.F.);
#566=CARTESIAN_POINT('',(29.6164,0.,5.77596));
#567=DIRECTION('',(0.,0.,-1.));
#568=DIRECTION('',(-1.,0.,0.));
#569=AXIS2_PLACEMENT_3D('',#566,#567,#568);
#570=PLANE('',#569);
#571=ORIENTED_EDGE('',*,*,#561,.F.);
#572=EDGE_LOOP('',(#571));
#573=FACE_BOUND('',#572,.T.);
#574=CARTESIAN_POINT('',(25.4,0.,5.77596));
#575=DIRECTION('',(0.,0.,1.));
#576=DIRECTION('',(1.,0.,0.));
#577=AXIS2_PLACEMENT_3D('',#574,#575,#576);
#578=CIRCLE('',#577,4.93618496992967);
#579=CARTESIAN_POINT('',(30.3361849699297,0.,5.77596));
#580=VERTEX_POINT('',#579);
#581=EDGE_CURVE('E307',#580,#580,#578,.T.);
#582=ORIENTED_EDGE('',*,*,#581,.T.);
#583=EDGE_LOOP('',(#582));
#584=FACE_BOUND('',#583,.T.);
#585=ADVANCED_FACE('F179',(#573,#584),#570,.F.);
#586=CARTESIAN_POINT('',(25.4,0.,12.7));
#587=DIRECTION('',(0.,0.,1.));
#588=DIRECTION('',(1.,0.,0.));
#589=AXIS2_PLACEMENT_3D('',#586,#587,#588);
#590=CONICAL_SURFACE('',#589,5.1435,0.0299323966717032);
#591=ORIENTED_EDGE('',*,*,#581,.F.);
#592=EDGE_LOOP('',(#591));
#593=FACE_BOUND('',#592,.T.);
#594=ORIENTED_EDGE('',*,*,#137,.T.);
#595=EDGE_LOOP('',(#594));
#596=FACE_BOUND('',#595,.T.);
#597=ADVANCED_FACE('F183',(#593,#596),#590,.F.);
#598=CARTESIAN_POINT('',(8.128,0.,12.7));
#599=DIRECTION('',(0.,0.,1.));
#600=DIRECTION('',(1.,0.,0.));
#601=AXIS2_PLACEMENT_3D('',#598,#599,#600);
#602=CYLINDRICAL_SURFACE('',#601,4.2164);
#603=CARTESIAN_POINT('',(11.50747,-2.5213511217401,-2.36128521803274));
#604=CARTESIAN_POINT('',(11.5536911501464,-2.45939625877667,-2.42741459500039));
#605=CARTESIAN_POINT('',(11.5993224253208,-2.3946798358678,-2.49132418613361));
#606=CARTESIAN_POINT('',(11.6887383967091,-2.2595909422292,-2.6144843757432));
#607=CARTESIAN_POINT('',(11.7325206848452,-2.18921142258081,-2.67372898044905));
#608=CARTESIAN_POINT('',(11.8604509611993,-1.96870298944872,-2.84460579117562));
#609=CARTESIAN_POINT('',(11.9405814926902,-1.80998307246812,-2.94853981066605));
#610=CARTESIAN_POINT('',(12.0712383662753,-1.5006646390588,-3.11547277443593));
#611=CARTESIAN_POINT('',(12.1244867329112,-1.35338066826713,-3.18243952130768));
#612=CARTESIAN_POINT('',(12.19270992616,-1.12363255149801,-3.26756774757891));
#613=CARTESIAN_POINT('',(12.2134953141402,-1.04565709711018,-3.29337305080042));
#614=CARTESIAN_POINT('',(12.2508181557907,-0.887140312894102,-3.33956081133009));
#615=CARTESIAN_POINT('',(12.2673574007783,-0.806600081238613,-3.35994555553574));
#616=CARTESIAN_POINT('',(12.2959449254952,-0.642828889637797,-3.39510244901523));
#617=CARTESIAN_POINT('',(12.3079565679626,-0.559581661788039,-3.40982882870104));
#618=CARTESIAN_POINT('',(12.3270149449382,-0.391708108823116,-3.43316504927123));
#619=CARTESIAN_POINT('',(12.3340639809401,-0.307082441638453,-3.44177772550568));
#620=CARTESIAN_POINT('',(12.3430295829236,-0.137101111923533,-3.4527286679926));
#621=CARTESIAN_POINT('',(12.3449433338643,-0.0517450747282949,-3.45506349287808));
#622=CARTESIAN_POINT('',(12.3435897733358,0.118836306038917,-3.45341073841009));
#623=CARTESIAN_POINT('',(12.3403229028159,0.204061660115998,-3.44942369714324));
#624=CARTESIAN_POINT('',(12.3240986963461,0.440075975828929,-3.42960075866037));
#625=CARTESIAN_POINT('',(12.3055593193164,0.589990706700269,-3.40693494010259));
#626=CARTESIAN_POINT('',(12.2536092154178,0.882934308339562,-3.3430287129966));
#627=CARTESIAN_POINT('',(12.2202011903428,1.02596442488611,-3.30179167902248));
#628=CARTESIAN_POINT('',(12.1391635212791,1.30805152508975,-3.20081726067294));
#629=CARTESIAN_POINT('',(12.0910101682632,1.44670956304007,-3.1403949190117));
#630=CARTESIAN_POINT('',(11.9839151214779,1.71185391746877,-3.00411435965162));
#631=CARTESIAN_POINT('',(11.9249593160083,1.83832397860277,-2.92823593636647));
#632=CARTESIAN_POINT('',(11.8074875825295,2.06233868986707,-2.774105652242));
#633=CARTESIAN_POINT('',(11.7499183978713,2.16150425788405,-2.69745592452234));
#634=CARTESIAN_POINT('',(11.6310581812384,2.34924119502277,-2.53558274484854));
#635=CARTESIAN_POINT('',(11.5697842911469,2.43785645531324,-2.45039773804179));
#636=CARTESIAN_POINT('',(11.50747,2.5213511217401,-2.36128521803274));
#637=B_SPLINE_CURVE_WITH_KNOTS('',3,(#603,#604,#605,#606,#607,#608,#609,#610,#611,#612,#613,
#614,#615,#616,#617,#618,#619,#620,#621,#622,#623,#624,#625,#626,#627,#628,#629,#630,#631,#632,
#633,#634,#635,#636),.UNSPECIFIED.,.F.,.F.,(4,2,2,2,2,2,2,2,2,2,2,2,2,2,2,2,4),(0.,
0.305036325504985,0.610458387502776,1.22514584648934,1.73389759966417,1.98779546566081,
2.24158604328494,2.49738831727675,2.75307188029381,3.00889557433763,3.26469749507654,
3.7206407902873,4.17650126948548,4.65092435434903,5.1259716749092,5.53902165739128,
5.95028832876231),.UNSPECIFIED.);
#638=CARTESIAN_POINT('',(11.50747,-2.5213511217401,-2.36128521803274));
#639=VERTEX_POINT('',#638);
#640=CARTESIAN_POINT('',(11.50747,2.5213511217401,-2.36128521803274));
#641=VERTEX_POINT('',#640);
#642=EDGE_CURVE('E44',#639,#641,#637,.T.);
#643=ORIENTED_EDGE('',*,*,#642,.T.);
#644=CARTESIAN_POINT('',(11.984908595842,1.7036094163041,-3.89251097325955));
#645=CARTESIAN_POINT('',(11.9627752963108,1.7536992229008,-3.83037002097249));
#646=CARTESIAN_POINT('',(11.940387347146,1.80176487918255,-3.76673936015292));
#647=CARTESIAN_POINT('',(11.8953754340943,1.89408576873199,-3.63692881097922));
#648=CARTESIAN_POINT('',(11.8727516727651,1.93834401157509,-3.57075099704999));
#649=CARTESIAN_POINT('',(11.8048639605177,2.06591257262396,-3.36883451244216));
#650=CARTESIAN_POINT('',(11.7596017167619,2.14397704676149,-3.22976317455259));
#651=CARTESIAN_POINT('',(11.6687354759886,2.29107766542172,-2.93804314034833));
#652=CARTESIAN_POINT('',(11.6232189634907,2.35950222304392,-2.78506317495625));
#653=CARTESIAN_POINT('',(11.5359434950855,2.48389162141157,-2.47300263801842));
#654=CARTESIAN_POINT('',(11.4941864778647,2.53985005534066,-2.31391897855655));
#655=CARTESIAN_POINT('',(11.4162317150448,2.63999881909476,-1.99041872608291));
#656=CARTESIAN_POINT('',(11.3800445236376,2.68416692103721,-1.82599270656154));
#657=CARTESIAN_POINT('',(11.3152337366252,2.76081345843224,-1.4929957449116));
#658=CARTESIAN_POINT('',(11.2866085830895,2.79329430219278,-1.32442566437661));
#659=CARTESIAN_POINT('',(11.2383960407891,2.84689163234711,-0.981644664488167));
#660=CARTESIAN_POINT('',(11.2189448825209,2.86783754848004,-0.807387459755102));
#661=CARTESIAN_POINT('',(11.1912173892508,2.89743803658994,-0.456937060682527));
#662=CARTESIAN_POINT('',(11.1829404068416,2.90609332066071,-0.280743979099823));
#663=CARTESIAN_POINT('',(11.1782805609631,2.91098436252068,0.0718049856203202));
#664=CARTESIAN_POINT('',(11.1818862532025,2.90723207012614,0.248160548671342));
#665=CARTESIAN_POINT('',(11.2006494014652,2.88739274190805,0.599543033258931));
#666=CARTESIAN_POINT('',(11.2158066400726,2.87130593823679,0.774569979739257));
#667=CARTESIAN_POINT('',(11.2541660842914,2.82945483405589,1.10254207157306));
#668=CARTESIAN_POINT('',(11.2762882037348,2.80496333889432,1.25578128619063));
#669=CARTESIAN_POINT('',(11.3274251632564,2.74649150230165,1.55927709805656));
#670=CARTESIAN_POINT('',(11.3564406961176,2.71251020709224,1.70953339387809));
#671=CARTESIAN_POINT('',(11.419933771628,2.63509043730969,2.00613468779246));
#672=CARTESIAN_POINT('',(11.4544027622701,2.59166673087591,2.15248539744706));
#673=CARTESIAN_POINT('',(11.527446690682,2.49508714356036,2.44082752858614));
#674=CARTESIAN_POINT('',(11.5660195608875,2.44193615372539,2.58282109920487));
#675=CARTESIAN_POINT('',(11.6237031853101,2.3577677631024,2.78411958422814));
#676=CARTESIAN_POINT('',(11.6417076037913,2.33087971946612,2.84549440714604));
#677=CARTESIAN_POINT('',(11.6781659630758,2.27496505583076,2.96721758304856));
#678=CARTESIAN_POINT('',(11.6966203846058,2.24593607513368,3.02756470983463));
#679=CARTESIAN_POINT('',(11.746237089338,2.16561189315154,3.18685872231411));
#680=CARTESIAN_POINT('',(11.7776772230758,2.11236338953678,3.284745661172));
#681=CARTESIAN_POINT('',(11.8408349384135,1.99927016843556,3.47654034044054));
#682=CARTESIAN_POINT('',(11.8725524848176,1.9394262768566,3.57044857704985));
#683=CARTESIAN_POINT('',(11.9355381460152,1.81264554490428,3.75317803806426));
#684=CARTESIAN_POINT('',(11.966807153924,1.74572600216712,3.84201088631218));
#685=CARTESIAN_POINT('',(12.0281667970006,1.60396025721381,4.0134742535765));
#686=CARTESIAN_POINT('',(12.0582587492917,1.52912328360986,4.09611180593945));
#687=CARTESIAN_POINT('',(12.0997649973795,1.41577894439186,4.20860195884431));
#688=CARTESIAN_POINT('',(12.1120647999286,1.38082769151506,4.24173576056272));
#689=CARTESIAN_POINT('',(12.1361688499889,1.30921266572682,4.30632792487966));
#690=CARTESIAN_POINT('',(12.1479728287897,1.27254798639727,4.33778538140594));
#691=CARTESIAN_POINT('',(12.1594765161,1.23500042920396,4.36829777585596));
#692=B_SPLINE_CURVE_WITH_KNOTS('',3,(#644,#645,#646,#647,#648,#649,#650,#651,#652,#653,#654,
#655,#656,#657,#658,#659,#660,#661,#662,#663,#664,#665,#666,#667,#668,#669,#670,#671,#672,#673,
#674,#675,#676,#677,#678,#679,#680,#681,#682,#683,#684,#685,#686,#687,#688,#689,#690,#691),
.UNSPECIFIED.,.F.,.F.,(4,2,2,2,2,2,2,2,2,2,2,2,2,2,2,2,2,2,2,2,2,2,2,4),(0.,0.248382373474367,
0.49656657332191,0.993133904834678,1.51348735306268,2.03410761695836,2.55570256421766,
3.07718996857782,3.60619477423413,4.13516892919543,4.66363377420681,5.19208867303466,
5.66186921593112,6.13169699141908,6.60079516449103,7.06965811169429,7.27777305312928,
7.48612100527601,7.83322897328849,8.18029352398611,8.52652841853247,8.87236409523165,
9.0214308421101,9.17057735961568),.UNSPECIFIED.);
#693=CARTESIAN_POINT('',(11.50747,2.5213511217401,2.36128521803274));
#694=VERTEX_POINT('',#693);
#695=EDGE_CURVE('E11',#641,#694,#692,.T.);
#696=ORIENTED_EDGE('',*,*,#695,.T.);
#697=CARTESIAN_POINT('',(11.50747,2.5213511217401,2.36128521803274));
#698=CARTESIAN_POINT('',(11.5536911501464,2.45939625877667,2.42741459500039));
#699=CARTESIAN_POINT('',(11.5993224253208,2.3946798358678,2.49132418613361));
#700=CARTESIAN_POINT('',(11.6887383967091,2.2595909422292,2.61448437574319));
#701=CARTESIAN_POINT('',(11.7325206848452,2.18921142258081,2.67372898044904));
#702=CARTESIAN_POINT('',(11.8604509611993,1.96870298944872,2.84460579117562));
#703=CARTESIAN_POINT('',(11.9405814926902,1.80998307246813,2.94853981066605));
#704=CARTESIAN_POINT('',(12.0712383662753,1.5006646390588,3.11547277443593));
#705=CARTESIAN_POINT('',(12.1244867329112,1.35338066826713,3.18243952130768));
#706=CARTESIAN_POINT('',(12.19270992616,1.12363255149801,3.2675677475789));
#707=CARTESIAN_POINT('',(12.2134953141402,1.04565709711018,3.29337305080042));
#708=CARTESIAN_POINT('',(12.2508181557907,0.887140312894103,3.33956081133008));
#709=CARTESIAN_POINT('',(12.2673574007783,0.806600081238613,3.35994555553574));
#710=CARTESIAN_POINT('',(12.2959449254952,0.642828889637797,3.39510244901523));
#711=CARTESIAN_POINT('',(12.3079565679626,0.559581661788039,3.40982882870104));
#712=CARTESIAN_POINT('',(12.3270149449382,0.391708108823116,3.43316504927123));
#713=CARTESIAN_POINT('',(12.3340639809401,0.307082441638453,3.44177772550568));
#714=CARTESIAN_POINT('',(12.3430295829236,0.137101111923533,3.4527286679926));
#715=CARTESIAN_POINT('',(12.3449433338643,0.0517450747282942,3.45506349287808));
#716=CARTESIAN_POINT('',(12.3435897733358,-0.118836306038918,3.45341073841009));
#717=CARTESIAN_POINT('',(12.3403229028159,-0.204061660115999,3.44942369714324));
#718=CARTESIAN_POINT('',(12.3240986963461,-0.44007597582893,3.42960075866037));
#719=CARTESIAN_POINT('',(12.3055593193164,-0.58999070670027,3.40693494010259));
#720=CARTESIAN_POINT('',(12.2536092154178,-0.882934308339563,3.3430287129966));
#721=CARTESIAN_POINT('',(12.2202011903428,-1.02596442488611,3.30179167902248));
#722=CARTESIAN_POINT('',(12.1391635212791,-1.30805152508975,3.20081726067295));
#723=CARTESIAN_POINT('',(12.0910101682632,-1.44670956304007,3.14039491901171));
#724=CARTESIAN_POINT('',(11.9839151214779,-1.71185391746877,3.00411435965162));
#725=CARTESIAN_POINT('',(11.9249593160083,-1.83832397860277,2.92823593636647));
#726=CARTESIAN_POINT('',(11.8074875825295,-2.06233868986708,2.774105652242));
#727=CARTESIAN_POINT('',(11.7499183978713,-2.16150425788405,2.69745592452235));
#728=CARTESIAN_POINT('',(11.6310581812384,-2.34924119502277,2.53558274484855));
#729=CARTESIAN_POINT('',(11.5697842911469,-2.43785645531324,2.4503977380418));
#730=CARTESIAN_POINT('',(11.50747,-2.5213511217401,2.36128521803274));
#731=B_SPLINE_CURVE_WITH_KNOTS('',3,(#697,#698,#699,#700,#701,#702,#703,#704,#705,#706,#707,
#708,#709,#710,#711,#712,#713,#714,#715,#716,#717,#718,#719,#720,#721,#722,#723,#724,#725,#726,
#727,#728,#729,#730),.UNSPECIFIED.,.F.,.F.,(4,2,2,2,2,2,2,2,2,2,2,2,2,2,2,2,4),(0.,
0.305036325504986,0.610458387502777,1.22514584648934,1.73389759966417,1.98779546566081,
2.24158604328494,2.49738831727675,2.75307188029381,3.00889557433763,3.26469749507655,
3.72064079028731,4.17650126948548,4.65092435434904,5.1259716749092,5.53902165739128,
5.95028832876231),.UNSPECIFIED.);
#732=CARTESIAN_POINT('',(11.50747,-2.5213511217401,2.36128521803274));
#733=VERTEX_POINT('',#732);
#734=EDGE_CURVE('E197',#694,#733,#731,.T.);
#735=ORIENTED_EDGE('',*,*,#734,.T.);
#736=CARTESIAN_POINT('',(11.984908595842,-1.7036094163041,3.89251097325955));
#737=CARTESIAN_POINT('',(11.9627752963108,-1.7536992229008,3.83037002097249));
#738=CARTESIAN_POINT('',(11.940387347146,-1.80176487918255,3.76673936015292));
#739=CARTESIAN_POINT('',(11.8953754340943,-1.89408576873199,3.63692881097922));
#740=CARTESIAN_POINT('',(11.8727516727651,-1.9383440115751,3.57075099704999));
#741=CARTESIAN_POINT('',(11.8048639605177,-2.06591257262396,3.36883451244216));
#742=CARTESIAN_POINT('',(11.7596017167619,-2.14397704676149,3.22976317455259));
#743=CARTESIAN_POINT('',(11.6687354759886,-2.29107766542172,2.93804314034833));
#744=CARTESIAN_POINT('',(11.6232189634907,-2.35950222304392,2.78506317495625));
#745=CARTESIAN_POINT('',(11.5359434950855,-2.48389162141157,2.47300263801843));
#746=CARTESIAN_POINT('',(11.4941864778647,-2.53985005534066,2.31391897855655));
#747=CARTESIAN_POINT('',(11.4162317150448,-2.63999881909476,1.99041872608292));
#748=CARTESIAN_POINT('',(11.3800445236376,-2.68416692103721,1.82599270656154));
#749=CARTESIAN_POINT('',(11.3152337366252,-2.76081345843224,1.4929957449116));
#750=CARTESIAN_POINT('',(11.2866085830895,-2.79329430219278,1.32442566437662));
#751=CARTESIAN_POINT('',(11.2383960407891,-2.84689163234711,0.98164466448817));
#752=CARTESIAN_POINT('',(11.2189448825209,-2.86783754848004,0.807387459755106));
#753=CARTESIAN_POINT('',(11.1912173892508,-2.89743803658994,0.45693706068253));
#754=CARTESIAN_POINT('',(11.1829404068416,-2.90609332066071,0.280743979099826));
#755=CARTESIAN_POINT('',(11.1782805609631,-2.91098436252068,-0.0718049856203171));
#756=CARTESIAN_POINT('',(11.1818862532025,-2.90723207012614,-0.248160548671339));
#757=CARTESIAN_POINT('',(11.2006494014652,-2.88739274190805,-0.599543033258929));
#758=CARTESIAN_POINT('',(11.2158066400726,-2.87130593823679,-0.774569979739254));
#759=CARTESIAN_POINT('',(11.2541660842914,-2.82945483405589,-1.10254207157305));
#760=CARTESIAN_POINT('',(11.2762882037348,-2.80496333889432,-1.25578128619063));
#761=CARTESIAN_POINT('',(11.3274251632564,-2.74649150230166,-1.55927709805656));
#762=CARTESIAN_POINT('',(11.3564406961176,-2.71251020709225,-1.70953339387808));
#763=CARTESIAN_POINT('',(11.419933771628,-2.63509043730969,-2.00613468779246));
#764=CARTESIAN_POINT('',(11.4544027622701,-2.59166673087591,-2.15248539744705));
#765=CARTESIAN_POINT('',(11.527446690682,-2.49508714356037,-2.44082752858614));
#766=CARTESIAN_POINT('',(11.5660195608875,-2.44193615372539,-2.58282109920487));
#767=CARTESIAN_POINT('',(11.6237031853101,-2.3577677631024,-2.78411958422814));
#768=CARTESIAN_POINT('',(11.6417076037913,-2.33087971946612,-2.84549440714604));
#769=CARTESIAN_POINT('',(11.6781659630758,-2.27496505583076,-2.96721758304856));
#770=CARTESIAN_POINT('',(11.6966203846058,-2.24593607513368,-3.02756470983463));
#771=CARTESIAN_POINT('',(11.746237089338,-2.16561189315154,-3.18685872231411));
#772=CARTESIAN_POINT('',(11.7776772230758,-2.11236338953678,-3.284745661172));
#773=CARTESIAN_POINT('',(11.8408349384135,-1.99927016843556,-3.47654034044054));
#774=CARTESIAN_POINT('',(11.8725524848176,-1.9394262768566,-3.57044857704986));
#775=CARTESIAN_POINT('',(11.9355381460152,-1.81264554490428,-3.75317803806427));
#776=CARTESIAN_POINT('',(11.966807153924,-1.74572600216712,-3.84201088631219));
#777=CARTESIAN_POINT('',(12.0281667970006,-1.60396025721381,-4.0134742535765));
#778=CARTESIAN_POINT('',(12.0582587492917,-1.52912328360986,-4.09611180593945));
#779=CARTESIAN_POINT('',(12.0997649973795,-1.41577894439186,-4.20860195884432));
#780=CARTESIAN_POINT('',(12.1120647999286,-1.38082769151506,-4.24173576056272));
#781=CARTESIAN_POINT('',(12.1361688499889,-1.30921266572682,-4.30632792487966));
#782=CARTESIAN_POINT('',(12.1479728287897,-1.27254798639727,-4.33778538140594));
#783=CARTESIAN_POINT('',(12.1594765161,-1.23500042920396,-4.36829777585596));
#784=B_SPLINE_CURVE_WITH_KNOTS('',3,(#736,#737,#738,#739,#740,#741,#742,#743,#744,#745,#746,
#747,#748,#749,#750,#751,#752,#753,#754,#755,#756,#757,#758,#759,#760,#761,#762,#763,#764,#765,
#766,#767,#768,#769,#770,#771,#772,#773,#774,#775,#776,#777,#778,#779,#780,#781,#782,#783),
.UNSPECIFIED.,.F.,.F.,(4,2,2,2,2,2,2,2,2,2,2,2,2,2,2,2,2,2,2,2,2,2,2,4),(0.,0.248382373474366,
0.496566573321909,0.993133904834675,1.51348735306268,2.03410761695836,2.55570256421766,
3.07718996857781,3.60619477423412,4.13516892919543,4.66363377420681,5.19208867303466,
5.66186921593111,6.13169699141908,6.60079516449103,7.06965811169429,7.27777305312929,
7.48612100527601,7.8332289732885,8.18029352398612,8.52652841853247,8.87236409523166,
9.0214308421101,9.17057735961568),.UNSPECIFIED.);
#785=EDGE_CURVE('E154',#733,#639,#784,.T.);
#786=ORIENTED_EDGE('',*,*,#785,.T.);
#787=EDGE_LOOP('',(#643,#696,#735,#786));
#788=FACE_BOUND('',#787,.T.);
#789=CARTESIAN_POINT('',(8.128,0.,5.77596));
#790=DIRECTION('',(0.,0.,1.));
#791=DIRECTION('',(1.,0.,0.));
#792=AXIS2_PLACEMENT_3D('',#789,#790,#791);
#793=CIRCLE('',#792,4.2164);
#794=CARTESIAN_POINT('',(12.3444,0.,5.77596));
#795=VERTEX_POINT('',#794);
#796=EDGE_CURVE('E313',#795,#795,#793,.T.);
#797=ORIENTED_EDGE('',*,*,#796,.T.);
#798=EDGE_LOOP('',(#797));
#799=FACE_BOUND('',#798,.T.);
#800=CARTESIAN_POINT('',(8.128,0.,-5.77596));
#801=DIRECTION('',(0.,0.,-1.));
#802=DIRECTION('',(0.,1.,0.));
#803=AXIS2_PLACEMENT_3D('',#800,#801,#802);
#804=CIRCLE('',#803,4.21640000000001);
#805=CARTESIAN_POINT('',(8.128,4.21640000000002,-5.77596));
#806=VERTEX_POINT('',#805);
#807=EDGE_CURVE('E322',#806,#806,#804,.T.);
#808=ORIENTED_EDGE('',*,*,#807,.T.);
#809=EDGE_LOOP('',(#808));
#810=FACE_BOUND('',#809,.T.);
#811=ADVANCED_FACE('F186',(#788,#799,#810),#602,.F.);
#812=CARTESIAN_POINT('',(12.3444,0.,5.77596));
#813=DIRECTION('',(0.,0.,-1.));
#814=DIRECTION('',(-1.,0.,0.));
#815=AXIS2_PLACEMENT_3D('',#812,#813,#814);
#816=PLANE('',#815);
#817=ORIENTED_EDGE('',*,*,#796,.F.);
#818=EDGE_LOOP('',(#817));
#819=FACE_BOUND('',#818,.T.);
#820=CARTESIAN_POINT('',(8.128,0.,5.77596));
#821=DIRECTION('',(0.,0.,1.));
#822=DIRECTION('',(1.,0.,0.));
#823=AXIS2_PLACEMENT_3D('',#820,#821,#822);
#824=CIRCLE('',#823,4.93618496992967);
#825=CARTESIAN_POINT('',(13.0641849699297,0.,5.77596));
#826=VERTEX_POINT('',#825);
#827=EDGE_CURVE('E316',#826,#826,#824,.T.);
#828=ORIENTED_EDGE('',*,*,#827,.T.);
#829=EDGE_LOOP('',(#828));
#830=FACE_BOUND('',#829,.T.);
#831=ADVANCED_FACE('F191',(#819,#830),#816,.F.);
#832=CARTESIAN_POINT('',(8.128,0.,12.7));
#833=DIRECTION('',(0.,0.,1.));
#834=DIRECTION('',(1.,0.,0.));
#835=AXIS2_PLACEMENT_3D('',#832,#833,#834);
#836=CONICAL_SURFACE('',#835,5.1435,0.0299323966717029);
#837=ORIENTED_EDGE('',*,*,#827,.F.);
#838=EDGE_LOOP('',(#837));
#839=FACE_BOUND('',#838,.T.);
#840=ORIENTED_EDGE('',*,*,#126,.T.);
#841=EDGE_LOOP('',(#840));
#842=FACE_BOUND('',#841,.T.);
#843=ADVANCED_FACE('F234',(#839,#842),#836,.F.);
#844=CARTESIAN_POINT('',(12.3444,0.,-5.77596));
#845=DIRECTION('',(0.,0.,1.));
#846=DIRECTION('',(0.,-1.,0.));
#847=AXIS2_PLACEMENT_3D('',#844,#845,#846);
#848=PLANE('',#847);
#849=ORIENTED_EDGE('',*,*,#807,.F.);
#850=EDGE_LOOP('',(#849));
#851=FACE_BOUND('',#850,.T.);
#852=CARTESIAN_POINT('',(8.128,0.,-5.77596));
#853=DIRECTION('',(0.,0.,-1.));
#854=DIRECTION('',(0.,1.,0.));
#855=AXIS2_PLACEMENT_3D('',#852,#853,#854);
#856=CIRCLE('',#855,4.93618496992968);
#857=CARTESIAN_POINT('',(8.128,4.93618496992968,-5.77596));
#858=VERTEX_POINT('',#857);
#859=EDGE_CURVE('E325',#858,#858,#856,.T.);
#860=ORIENTED_EDGE('',*,*,#859,.T.);
#861=EDGE_LOOP('',(#860));
#862=FACE_BOUND('',#861,.T.);
#863=ADVANCED_FACE('F231',(#851,#862),#848,.F.);
#864=CARTESIAN_POINT('',(8.128,0.,-12.7));
#865=DIRECTION('',(0.,0.,-1.));
#866=DIRECTION('',(0.,1.,0.));
#867=AXIS2_PLACEMENT_3D('',#864,#865,#866);
#868=CONICAL_SURFACE('',#867,5.1435,0.0299323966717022);
#869=ORIENTED_EDGE('',*,*,#859,.F.);
#870=EDGE_LOOP('',(#869));
#871=FACE_BOUND('',#870,.T.);
#872=ORIENTED_EDGE('',*,*,#227,.T.);
#873=EDGE_LOOP('',(#872));
#874=FACE_BOUND('',#873,.T.);
#875=ADVANCED_FACE('F218',(#871,#874),#868,.F.);
#876=CARTESIAN_POINT('',(39.44747,0.,0.));
#877=DIRECTION('',(1.,0.,0.));
#878=DIRECTION('',(0.,0.,-1.));
#879=AXIS2_PLACEMENT_3D('',#876,#877,#878);
#880=CYLINDRICAL_SURFACE('',#879,3.45439999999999);
#881=CARTESIAN_POINT('',(12.77747,0.,0.));
#882=DIRECTION('',(1.,0.,0.));
#883=DIRECTION('',(0.,0.,-1.));
#884=AXIS2_PLACEMENT_3D('',#881,#882,#883);
#885=CIRCLE('',#884,3.45439999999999);
#886=CARTESIAN_POINT('',(12.77747,0.,-3.45439999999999));
#887=VERTEX_POINT('',#886);
#888=EDGE_CURVE('E334',#887,#887,#885,.T.);
#889=ORIENTED_EDGE('',*,*,#888,.T.);
#890=EDGE_LOOP('',(#889));
#891=FACE_BOUND('',#890,.T.);
#892=CARTESIAN_POINT('',(11.50747,0.,0.));
#893=DIRECTION('',(1.,0.,0.));
#894=DIRECTION('',(0.,0.,-1.));
#895=AXIS2_PLACEMENT_3D('',#892,#893,#894);
#896=CIRCLE('',#895,3.45439999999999);
#897=EDGE_CURVE('E50',#733,#639,#896,.T.);
#898=ORIENTED_EDGE('',*,*,#897,.F.);
#899=ORIENTED_EDGE('',*,*,#734,.F.);
#900=EDGE_CURVE('E331',#641,#694,#896,.T.);
#901=ORIENTED_EDGE('',*,*,#900,.F.);
#902=ORIENTED_EDGE('',*,*,#642,.F.);
#903=EDGE_LOOP('',(#898,#899,#901,#902));
#904=FACE_BOUND('',#903,.T.);
#905=ADVANCED_FACE('F213',(#891,#904),#880,.F.);
#906=CARTESIAN_POINT('',(11.50747,0.,0.));
#907=DIRECTION('',(1.,0.,0.));
#908=DIRECTION('',(0.,0.,-1.));
#909=AXIS2_PLACEMENT_3D('',#906,#907,#908);
#910=CONICAL_SURFACE('',#909,3.45439999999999,1.02974425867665);
#911=ORIENTED_EDGE('',*,*,#900,.T.);
#912=ORIENTED_EDGE('',*,*,#695,.F.);
#913=EDGE_LOOP('',(#911,#912));
#914=FACE_BOUND('',#913,.T.);
#915=ADVANCED_FACE('F217',(#914),#910,.F.);
#916=ORIENTED_EDGE('',*,*,#897,.T.);
#917=ORIENTED_EDGE('',*,*,#785,.F.);
#918=EDGE_LOOP('',(#916,#917));
#919=FACE_BOUND('',#918,.T.);
#920=ADVANCED_FACE('F226',(#919),#910,.F.);
#921=CARTESIAN_POINT('',(12.77747,3.45439999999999,0.));
#922=DIRECTION('',(-1.,0.,0.));
#923=DIRECTION('',(0.,0.,1.));
#924=AXIS2_PLACEMENT_3D('',#921,#922,#923);
#925=PLANE('',#924);
#926=ORIENTED_EDGE('',*,*,#888,.F.);
#927=EDGE_LOOP('',(#926));
#928=FACE_BOUND('',#927,.T.);
#929=CARTESIAN_POINT('',(12.77747,0.,0.));
#930=DIRECTION('',(1.,0.,0.));
#931=DIRECTION('',(0.,0.,-1.));
#932=AXIS2_PLACEMENT_3D('',#929,#930,#931);
#933=CIRCLE('',#932,3.96874999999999);
#934=CARTESIAN_POINT('',(12.77747,0.,-3.96874999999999));
#935=VERTEX_POINT('',#934);
#936=EDGE_CURVE('E337',#935,#935,#933,.T.);
#937=ORIENTED_EDGE('',*,*,#936,.T.);
#938=EDGE_LOOP('',(#937));
#939=FACE_BOUND('',#938,.T.);
#940=ADVANCED_FACE('F220',(#928,#939),#925,.F.);
#941=CARTESIAN_POINT('',(39.44747,0.,0.));
#942=DIRECTION('',(1.,0.,0.));
#943=DIRECTION('',(0.,0.,-1.));
#944=AXIS2_PLACEMENT_3D('',#941,#942,#943);
#945=CYLINDRICAL_SURFACE('',#944,3.96875);
#946=ORIENTED_EDGE('',*,*,#369,.T.);
#947=EDGE_LOOP('',(#946));
#948=FACE_BOUND('',#947,.T.);
#949=ORIENTED_EDGE('',*,*,#936,.F.);
#950=EDGE_LOOP('',(#949));
#951=FACE_BOUND('',#950,.T.);
#952=ADVANCED_FACE('F342',(#948,#951),#945,.F.);
#953=CLOSED_SHELL('',(#46,#113,#166,#190,#214,#249,#273,#290,#304,#316,#344,#356,#384,#545,#565,
#585,#597,#811,#831,#843,#863,#875,#905,#915,#920,#940,#952));
#954=MANIFOLD_SOLID_BREP('B2',#953);
#955=ADVANCED_BREP_SHAPE_REPRESENTATION('',(#18,#954),#14);
#956=SHAPE_DEFINITION_REPRESENTATION(#9,#955);
ENDSEC;
END-ISO-10303-21;
